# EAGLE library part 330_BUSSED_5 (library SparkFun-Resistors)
5 x 330Ω resistor network A resistor is a passive two-terminal electrical component that implements electrical resistance as a circuit element. Resistors act to reduce current flow, and, at the same time, act to lower voltage levels within circuits. - Wikipedia This is a bussed or ladder network.

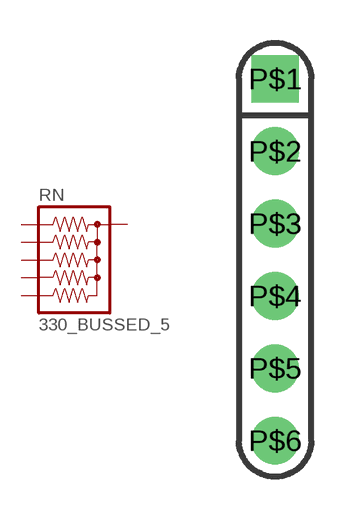
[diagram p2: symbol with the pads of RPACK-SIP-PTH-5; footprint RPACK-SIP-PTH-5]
Designator prefix RN

## 330_BUSSED_5 (SF_SKU: COM-10856; VALUE: 330)  [RPACK-SIP-PTH-5]
P$1  1  pas
P$2  2  pas
P$3  3  pas
P$4  4  pas
P$5  5  pas
P$6  6  pas

## Footprint RPACK-SIP-PTH-5 (pad centres in mm)
Based on this datasheet.
drill 0.8 pad 1.676 square: P$1 0,0
drill 0.8 pad 1.676: P$2 0,-2.54; P$3 0,-5.08; P$4 0,-7.62; P$5 0,-10.16; P$6 0,-12.7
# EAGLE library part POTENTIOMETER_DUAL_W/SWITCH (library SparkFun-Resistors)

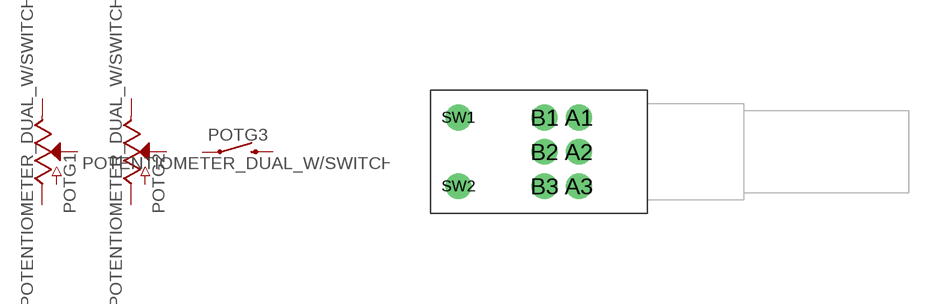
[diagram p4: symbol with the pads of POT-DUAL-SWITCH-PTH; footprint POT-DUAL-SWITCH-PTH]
Designator prefix POT; gates G2=POTENTIOMETER G1=POTENTIOMETER G3=SWITCH-MOMENTARY

## POTENTIOMETER_DUAL_W/SWITCH (PROD_ID: RES-13814; VALUE: 20k)  [POT-DUAL-SWITCH-PTH]
A1  G1:A  pas
A2  G1:S  pas
A3  G1:E  pas
B1  G2:A  pas
B2  G2:S  pas
B3  G2:E  pas
SW1  G3:1  pas
SW2  G3:2  pas

## Footprint POT-DUAL-SWITCH-PTH (pad centres in mm)
drill 1 pad 1.88: A1 2.54,2.5; A2 2.54,0; A3 2.54,-2.5; B1 0.04,2.5; B2 0.04,0; B3 0.04,-2.5; SW1 -6.21,2.5; SW2 -6.21,-2.5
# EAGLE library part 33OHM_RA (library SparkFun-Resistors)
EXB-38V330JV Four Resistory Array - AEC-Q200 Certified

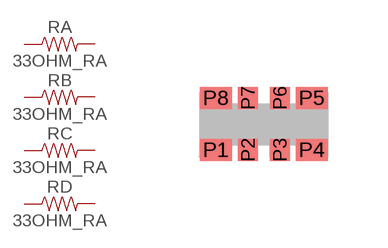
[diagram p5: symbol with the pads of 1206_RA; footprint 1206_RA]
Designator prefix R; gates A=RESISTOR B=RESISTOR C=RESISTOR D=RESISTOR

## 33OHM_RA-1206-1/16W-5% (PROD_ID: RES-15081; VALUE: 33)  [1206_RA]
P1  A:1  pas
P2  B:1  pas
P3  C:1  pas
P4  D:1  pas
P5  D:2  pas
P6  C:2  pas
P7  B:2  pas
P8  A:2  pas

## Footprint 1206_RA (pad centres in mm)
4 Resistor Array Total Size: 3.2mm x 1.6mm (1206) Pad Size: .5mm - .8mm x .55mm Pitch: .5mm
smd 0.8 x 0.55: P1 -1.2,-0.62; P4 1.2,-0.62; P5 1.2,0.68; P8 -1.2,0.68
smd 0.5 x 0.55: P2 -0.4,-0.62; P3 0.4,-0.62; P6 0.4,0.68; P7 -0.4,0.68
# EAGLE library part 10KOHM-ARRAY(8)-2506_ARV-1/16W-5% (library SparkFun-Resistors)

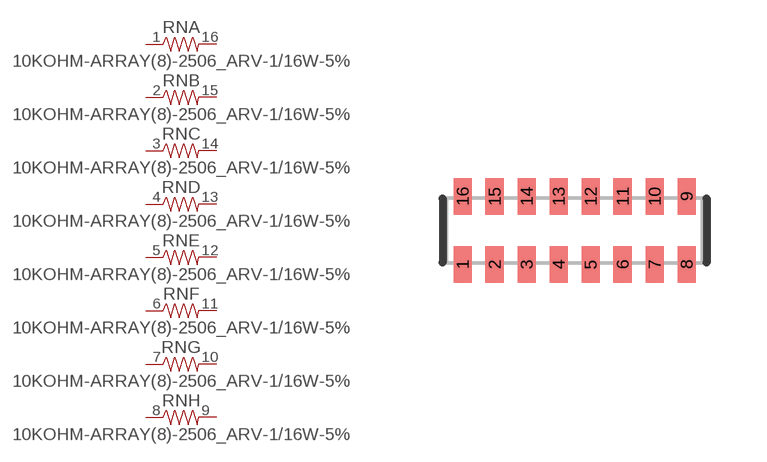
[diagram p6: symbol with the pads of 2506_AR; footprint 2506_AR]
Designator prefix RN; gates A=RESISTOR-PADS B=RESISTOR-PADS C=RESISTOR-PADS D=RESISTOR-PADS E=RESISTOR-PADS F=RESISTOR-PADS G=RESISTOR-PADS H=RESISTOR-PADS

## 10KOHM-ARRAY(8)-2506_ARV-1/16W-5% (PROD_ID: RES-14952; VALUE: 10K)  [2506_AR]
1  A:1  pas
2  B:1  pas
3  C:1  pas
4  D:1  pas
5  E:1  pas
6  F:1  pas
7  G:1  pas
8  H:1  pas
9  H:2  pas
10  G:2  pas
11  F:2  pas
12  E:2  pas
13  D:2  pas
14  C:2  pas
15  B:2  pas
16  A:2  pas

## Footprint 2506_AR (pad centres in mm)
smd 0.45 x 0.9: 1 -2.8,-0.85; 2 -2,-0.85; 3 -1.2,-0.85; 4 -0.4,-0.85; 5 0.4,-0.85; 6 1.2,-0.85; 7 2,-0.85; 8 2.8,-0.85; 9 2.8,0.85; 10 2,0.85; 11 1.2,0.85; 12 0.4,0.85; 13 -0.4,0.85; 14 -1.2,0.85; 15 -2,0.85; 16 -2.8,0.85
